# Generated deterministically by seda-macro-lef-normalizer-v1; recipe orfs-asap7-fakeram-m4-v1.
VERSION 5.8 ;
BUSBITCHARS "[]" ;
DIVIDERCHAR "/" ;

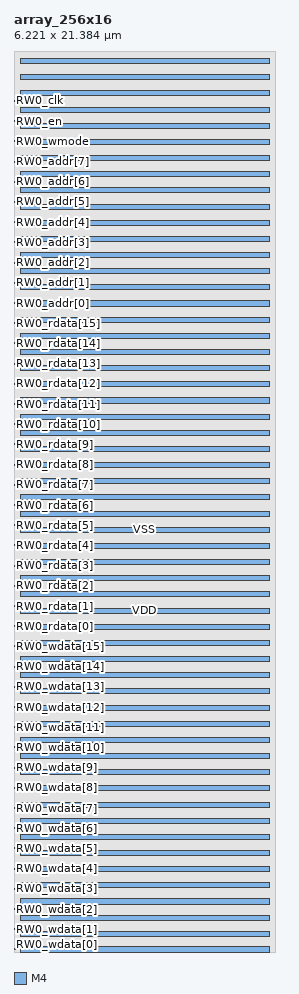
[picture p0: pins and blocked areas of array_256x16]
MACRO array_256x16
  FOREIGN array_256x16 0 0 ;
  CLASS BLOCK ;
  ORIGIN 0 0 ;
  SIZE 6.221 BY 21.384 ;
  SYMMETRY X Y R90 ;
  PIN RW0_wdata[0]
    DIRECTION INPUT ;
    USE SIGNAL ;
    SHAPE ABUTMENT ;
    PORT
      LAYER M4 ;
      RECT 0.000 0.048 0.084 0.072 ;
    END
  END RW0_wdata[0]
  PIN RW0_wdata[1]
    DIRECTION INPUT ;
    USE SIGNAL ;
    SHAPE ABUTMENT ;
    PORT
      LAYER M4 ;
      RECT 0.000 0.528 0.084 0.552 ;
    END
  END RW0_wdata[1]
  PIN RW0_wdata[2]
    DIRECTION INPUT ;
    USE SIGNAL ;
    SHAPE ABUTMENT ;
    PORT
      LAYER M4 ;
      RECT 0.000 1.008 0.084 1.032 ;
    END
  END RW0_wdata[2]
  PIN RW0_wdata[3]
    DIRECTION INPUT ;
    USE SIGNAL ;
    SHAPE ABUTMENT ;
    PORT
      LAYER M4 ;
      RECT 0.000 1.488 0.084 1.512 ;
    END
  END RW0_wdata[3]
  PIN RW0_wdata[4]
    DIRECTION INPUT ;
    USE SIGNAL ;
    SHAPE ABUTMENT ;
    PORT
      LAYER M4 ;
      RECT 0.000 1.968 0.084 1.992 ;
    END
  END RW0_wdata[4]
  PIN RW0_wdata[5]
    DIRECTION INPUT ;
    USE SIGNAL ;
    SHAPE ABUTMENT ;
    PORT
      LAYER M4 ;
      RECT 0.000 2.448 0.084 2.472 ;
    END
  END RW0_wdata[5]
  PIN RW0_wdata[6]
    DIRECTION INPUT ;
    USE SIGNAL ;
    SHAPE ABUTMENT ;
    PORT
      LAYER M4 ;
      RECT 0.000 2.928 0.084 2.952 ;
    END
  END RW0_wdata[6]
  PIN RW0_wdata[7]
    DIRECTION INPUT ;
    USE SIGNAL ;
    SHAPE ABUTMENT ;
    PORT
      LAYER M4 ;
      RECT 0.000 3.408 0.084 3.432 ;
    END
  END RW0_wdata[7]
  PIN RW0_wdata[8]
    DIRECTION INPUT ;
    USE SIGNAL ;
    SHAPE ABUTMENT ;
    PORT
      LAYER M4 ;
      RECT 0.000 3.888 0.084 3.912 ;
    END
  END RW0_wdata[8]
  PIN RW0_wdata[9]
    DIRECTION INPUT ;
    USE SIGNAL ;
    SHAPE ABUTMENT ;
    PORT
      LAYER M4 ;
      RECT 0.000 4.368 0.084 4.392 ;
    END
  END RW0_wdata[9]
  PIN RW0_wdata[10]
    DIRECTION INPUT ;
    USE SIGNAL ;
    SHAPE ABUTMENT ;
    PORT
      LAYER M4 ;
      RECT 0.000 4.848 0.084 4.872 ;
    END
  END RW0_wdata[10]
  PIN RW0_wdata[11]
    DIRECTION INPUT ;
    USE SIGNAL ;
    SHAPE ABUTMENT ;
    PORT
      LAYER M4 ;
      RECT 0.000 5.328 0.084 5.352 ;
    END
  END RW0_wdata[11]
  PIN RW0_wdata[12]
    DIRECTION INPUT ;
    USE SIGNAL ;
    SHAPE ABUTMENT ;
    PORT
      LAYER M4 ;
      RECT 0.000 5.808 0.084 5.832 ;
    END
  END RW0_wdata[12]
  PIN RW0_wdata[13]
    DIRECTION INPUT ;
    USE SIGNAL ;
    SHAPE ABUTMENT ;
    PORT
      LAYER M4 ;
      RECT 0.000 6.288 0.084 6.312 ;
    END
  END RW0_wdata[13]
  PIN RW0_wdata[14]
    DIRECTION INPUT ;
    USE SIGNAL ;
    SHAPE ABUTMENT ;
    PORT
      LAYER M4 ;
      RECT 0.000 6.768 0.084 6.792 ;
    END
  END RW0_wdata[14]
  PIN RW0_wdata[15]
    DIRECTION INPUT ;
    USE SIGNAL ;
    SHAPE ABUTMENT ;
    PORT
      LAYER M4 ;
      RECT 0.000 7.248 0.084 7.272 ;
    END
  END RW0_wdata[15]
  PIN RW0_rdata[0]
    DIRECTION OUTPUT ;
    USE SIGNAL ;
    SHAPE ABUTMENT ;
    PORT
      LAYER M4 ;
      RECT 0.000 7.728 0.084 7.752 ;
    END
  END RW0_rdata[0]
  PIN RW0_rdata[1]
    DIRECTION OUTPUT ;
    USE SIGNAL ;
    SHAPE ABUTMENT ;
    PORT
      LAYER M4 ;
      RECT 0.000 8.208 0.084 8.232 ;
    END
  END RW0_rdata[1]
  PIN RW0_rdata[2]
    DIRECTION OUTPUT ;
    USE SIGNAL ;
    SHAPE ABUTMENT ;
    PORT
      LAYER M4 ;
      RECT 0.000 8.688 0.084 8.712 ;
    END
  END RW0_rdata[2]
  PIN RW0_rdata[3]
    DIRECTION OUTPUT ;
    USE SIGNAL ;
    SHAPE ABUTMENT ;
    PORT
      LAYER M4 ;
      RECT 0.000 9.168 0.084 9.192 ;
    END
  END RW0_rdata[3]
  PIN RW0_rdata[4]
    DIRECTION OUTPUT ;
    USE SIGNAL ;
    SHAPE ABUTMENT ;
    PORT
      LAYER M4 ;
      RECT 0.000 9.648 0.084 9.672 ;
    END
  END RW0_rdata[4]
  PIN RW0_rdata[5]
    DIRECTION OUTPUT ;
    USE SIGNAL ;
    SHAPE ABUTMENT ;
    PORT
      LAYER M4 ;
      RECT 0.000 10.128 0.084 10.152 ;
    END
  END RW0_rdata[5]
  PIN RW0_rdata[6]
    DIRECTION OUTPUT ;
    USE SIGNAL ;
    SHAPE ABUTMENT ;
    PORT
      LAYER M4 ;
      RECT 0.000 10.608 0.084 10.632 ;
    END
  END RW0_rdata[6]
  PIN RW0_rdata[7]
    DIRECTION OUTPUT ;
    USE SIGNAL ;
    SHAPE ABUTMENT ;
    PORT
      LAYER M4 ;
      RECT 0.000 11.088 0.084 11.112 ;
    END
  END RW0_rdata[7]
  PIN RW0_rdata[8]
    DIRECTION OUTPUT ;
    USE SIGNAL ;
    SHAPE ABUTMENT ;
    PORT
      LAYER M4 ;
      RECT 0.000 11.568 0.084 11.592 ;
    END
  END RW0_rdata[8]
  PIN RW0_rdata[9]
    DIRECTION OUTPUT ;
    USE SIGNAL ;
    SHAPE ABUTMENT ;
    PORT
      LAYER M4 ;
      RECT 0.000 12.048 0.084 12.072 ;
    END
  END RW0_rdata[9]
  PIN RW0_rdata[10]
    DIRECTION OUTPUT ;
    USE SIGNAL ;
    SHAPE ABUTMENT ;
    PORT
      LAYER M4 ;
      RECT 0.000 12.528 0.084 12.552 ;
    END
  END RW0_rdata[10]
  PIN RW0_rdata[11]
    DIRECTION OUTPUT ;
    USE SIGNAL ;
    SHAPE ABUTMENT ;
    PORT
      LAYER M4 ;
      RECT 0.000 13.008 0.084 13.032 ;
    END
  END RW0_rdata[11]
  PIN RW0_rdata[12]
    DIRECTION OUTPUT ;
    USE SIGNAL ;
    SHAPE ABUTMENT ;
    PORT
      LAYER M4 ;
      RECT 0.000 13.488 0.084 13.512 ;
    END
  END RW0_rdata[12]
  PIN RW0_rdata[13]
    DIRECTION OUTPUT ;
    USE SIGNAL ;
    SHAPE ABUTMENT ;
    PORT
      LAYER M4 ;
      RECT 0.000 13.968 0.084 13.992 ;
    END
  END RW0_rdata[13]
  PIN RW0_rdata[14]
    DIRECTION OUTPUT ;
    USE SIGNAL ;
    SHAPE ABUTMENT ;
    PORT
      LAYER M4 ;
      RECT 0.000 14.448 0.084 14.472 ;
    END
  END RW0_rdata[14]
  PIN RW0_rdata[15]
    DIRECTION OUTPUT ;
    USE SIGNAL ;
    SHAPE ABUTMENT ;
    PORT
      LAYER M4 ;
      RECT 0.000 14.928 0.084 14.952 ;
    END
  END RW0_rdata[15]
  PIN RW0_addr[0]
    DIRECTION INPUT ;
    USE SIGNAL ;
    SHAPE ABUTMENT ;
    PORT
      LAYER M4 ;
      RECT 0.000 15.408 0.084 15.432 ;
    END
  END RW0_addr[0]
  PIN RW0_addr[1]
    DIRECTION INPUT ;
    USE SIGNAL ;
    SHAPE ABUTMENT ;
    PORT
      LAYER M4 ;
      RECT 0.000 15.888 0.084 15.912 ;
    END
  END RW0_addr[1]
  PIN RW0_addr[2]
    DIRECTION INPUT ;
    USE SIGNAL ;
    SHAPE ABUTMENT ;
    PORT
      LAYER M4 ;
      RECT 0.000 16.368 0.084 16.392 ;
    END
  END RW0_addr[2]
  PIN RW0_addr[3]
    DIRECTION INPUT ;
    USE SIGNAL ;
    SHAPE ABUTMENT ;
    PORT
      LAYER M4 ;
      RECT 0.000 16.848 0.084 16.872 ;
    END
  END RW0_addr[3]
  PIN RW0_addr[4]
    DIRECTION INPUT ;
    USE SIGNAL ;
    SHAPE ABUTMENT ;
    PORT
      LAYER M4 ;
      RECT 0.000 17.328 0.084 17.352 ;
    END
  END RW0_addr[4]
  PIN RW0_addr[5]
    DIRECTION INPUT ;
    USE SIGNAL ;
    SHAPE ABUTMENT ;
    PORT
      LAYER M4 ;
      RECT 0.000 17.808 0.084 17.832 ;
    END
  END RW0_addr[5]
  PIN RW0_addr[6]
    DIRECTION INPUT ;
    USE SIGNAL ;
    SHAPE ABUTMENT ;
    PORT
      LAYER M4 ;
      RECT 0.000 18.288 0.084 18.312 ;
    END
  END RW0_addr[6]
  PIN RW0_addr[7]
    DIRECTION INPUT ;
    USE SIGNAL ;
    SHAPE ABUTMENT ;
    PORT
      LAYER M4 ;
      RECT 0.000 18.768 0.084 18.792 ;
    END
  END RW0_addr[7]
  PIN RW0_wmode
    DIRECTION INPUT ;
    USE SIGNAL ;
    SHAPE ABUTMENT ;
    PORT
      LAYER M4 ;
      RECT 0.000 19.248 0.084 19.272 ;
    END
  END RW0_wmode
  PIN RW0_en
    DIRECTION INPUT ;
    USE SIGNAL ;
    SHAPE ABUTMENT ;
    PORT
      LAYER M4 ;
      RECT 0.000 19.728 0.084 19.752 ;
    END
  END RW0_en
  PIN RW0_clk
    DIRECTION INPUT ;
    USE SIGNAL ;
    SHAPE ABUTMENT ;
    PORT
      LAYER M4 ;
      RECT 0.000 20.208 0.084 20.232 ;
    END
  END RW0_clk
  PIN VSS
    DIRECTION INOUT ;
    USE GROUND ;
    PORT
      LAYER M4 ;
      RECT 0.156 0.000 6.065 0.120 ;
      RECT 0.156 0.756 6.065 0.876 ;
      RECT 0.156 1.524 6.065 1.644 ;
      RECT 0.156 2.292 6.065 2.412 ;
      RECT 0.156 3.060 6.065 3.180 ;
      RECT 0.156 3.828 6.065 3.948 ;
      RECT 0.156 4.596 6.065 4.716 ;
      RECT 0.156 5.364 6.065 5.484 ;
      RECT 0.156 6.132 6.065 6.252 ;
      RECT 0.156 6.900 6.065 7.020 ;
      RECT 0.156 7.668 6.065 7.788 ;
      RECT 0.156 8.436 6.065 8.556 ;
      RECT 0.156 9.204 6.065 9.324 ;
      RECT 0.156 9.972 6.065 10.092 ;
      RECT 0.156 10.740 6.065 10.860 ;
      RECT 0.156 11.508 6.065 11.628 ;
      RECT 0.156 12.276 6.065 12.396 ;
      RECT 0.156 13.044 6.065 13.164 ;
      RECT 0.156 13.812 6.065 13.932 ;
      RECT 0.156 14.580 6.065 14.700 ;
      RECT 0.156 15.348 6.065 15.468 ;
      RECT 0.156 16.116 6.065 16.236 ;
      RECT 0.156 16.884 6.065 17.004 ;
      RECT 0.156 17.652 6.065 17.772 ;
      RECT 0.156 18.420 6.065 18.540 ;
      RECT 0.156 19.188 6.065 19.308 ;
      RECT 0.156 19.956 6.065 20.076 ;
      RECT 0.156 20.724 6.065 20.844 ;
    END
  END VSS
  PIN VDD
    DIRECTION INOUT ;
    USE POWER ;
    PORT
      LAYER M4 ;
      RECT 0.156 0.372 6.065 0.492 ;
      RECT 0.156 1.140 6.065 1.260 ;
      RECT 0.156 1.908 6.065 2.028 ;
      RECT 0.156 2.676 6.065 2.796 ;
      RECT 0.156 3.444 6.065 3.564 ;
      RECT 0.156 4.212 6.065 4.332 ;
      RECT 0.156 4.980 6.065 5.100 ;
      RECT 0.156 5.748 6.065 5.868 ;
      RECT 0.156 6.516 6.065 6.636 ;
      RECT 0.156 7.284 6.065 7.404 ;
      RECT 0.156 8.052 6.065 8.172 ;
      RECT 0.156 8.820 6.065 8.940 ;
      RECT 0.156 9.588 6.065 9.708 ;
      RECT 0.156 10.356 6.065 10.476 ;
      RECT 0.156 11.124 6.065 11.244 ;
      RECT 0.156 11.892 6.065 12.012 ;
      RECT 0.156 12.660 6.065 12.780 ;
      RECT 0.156 13.428 6.065 13.548 ;
      RECT 0.156 14.196 6.065 14.316 ;
      RECT 0.156 14.964 6.065 15.084 ;
      RECT 0.156 15.732 6.065 15.852 ;
      RECT 0.156 16.500 6.065 16.620 ;
      RECT 0.156 17.268 6.065 17.388 ;
      RECT 0.156 18.036 6.065 18.156 ;
      RECT 0.156 18.804 6.065 18.924 ;
      RECT 0.156 19.572 6.065 19.692 ;
      RECT 0.156 20.340 6.065 20.460 ;
      RECT 0.156 21.108 6.065 21.228 ;
    END
  END VDD
  OBS
    LAYER M1 ;
    RECT 0 0 6.221 21.384 ;
    LAYER M2 ;
    RECT 0 0 6.221 21.384 ;
    LAYER M3 ;
    RECT 0 0 6.221 21.384 ;
  END
END array_256x16

END LIBRARY
